VERSION 5.8 ;
BUSBITCHARS "[]" ;
DIVIDERCHAR "/" ;
UNITS
    DATABASE MICRONS 1000 ;
END UNITS

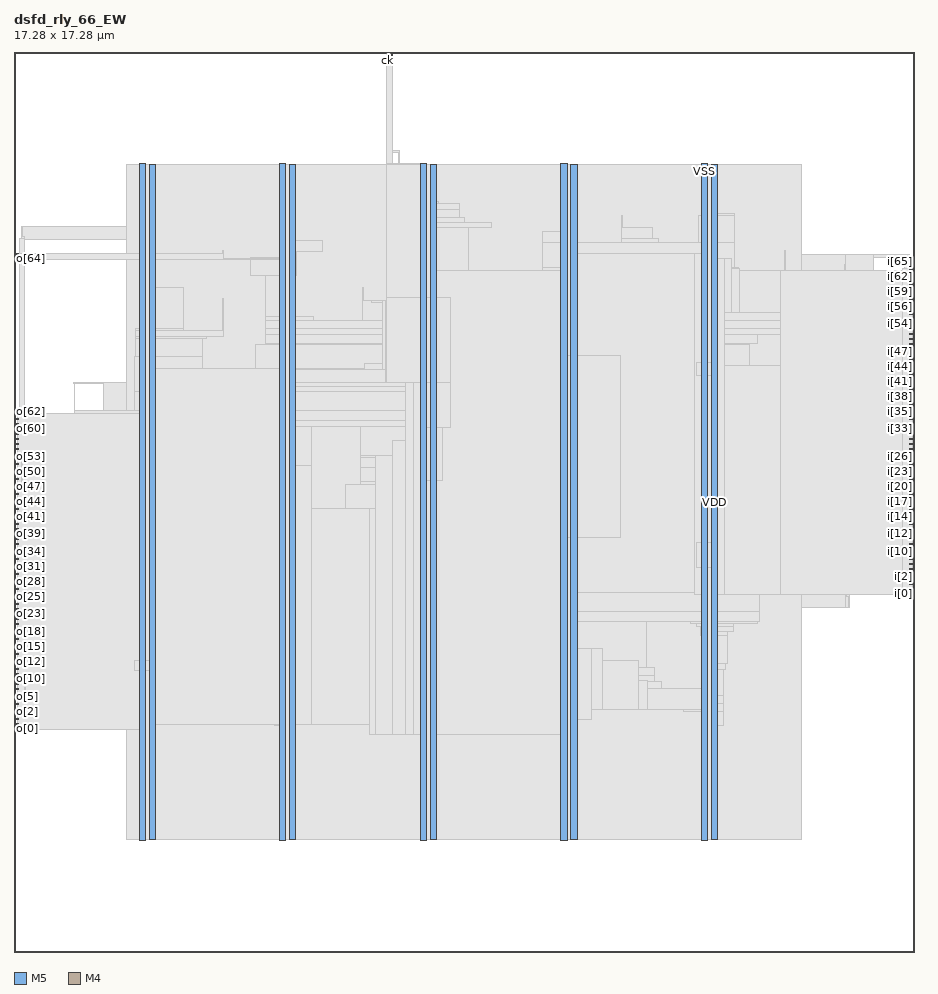
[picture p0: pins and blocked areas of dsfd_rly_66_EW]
MACRO dsfd_rly_66_EW
  FOREIGN dsfd_rly_66_EW 0 0 ;
  CLASS BLOCK ;
  SIZE 17.28 BY 17.28 ;
  PIN ck
    DIRECTION INPUT ;
    USE SIGNAL ;
    PORT
      LAYER M5 ;
        RECT  7.152 17.196 7.176 17.28 ;
    END
  END ck
  PIN i[0]
    DIRECTION INPUT ;
    USE SIGNAL ;
    PORT
      LAYER M4 ;
        RECT  17.196 6.864 17.28 6.888 ;
    END
  END i[0]
  PIN i[10]
    DIRECTION INPUT ;
    USE SIGNAL ;
    PORT
      LAYER M4 ;
        RECT  17.196 7.824 17.28 7.848 ;
    END
  END i[10]
  PIN i[11]
    DIRECTION INPUT ;
    USE SIGNAL ;
    PORT
      LAYER M4 ;
        RECT  17.196 7.92 17.28 7.944 ;
    END
  END i[11]
  PIN i[12]
    DIRECTION INPUT ;
    USE SIGNAL ;
    PORT
      LAYER M4 ;
        RECT  17.196 8.016 17.28 8.04 ;
    END
  END i[12]
  PIN i[13]
    DIRECTION INPUT ;
    USE SIGNAL ;
    PORT
      LAYER M4 ;
        RECT  17.196 8.112 17.28 8.136 ;
    END
  END i[13]
  PIN i[14]
    DIRECTION INPUT ;
    USE SIGNAL ;
    PORT
      LAYER M4 ;
        RECT  17.196 8.208 17.28 8.232 ;
    END
  END i[14]
  PIN i[15]
    DIRECTION INPUT ;
    USE SIGNAL ;
    PORT
      LAYER M4 ;
        RECT  17.196 8.304 17.28 8.328 ;
    END
  END i[15]
  PIN i[16]
    DIRECTION INPUT ;
    USE SIGNAL ;
    PORT
      LAYER M4 ;
        RECT  17.196 8.4 17.28 8.424 ;
    END
  END i[16]
  PIN i[17]
    DIRECTION INPUT ;
    USE SIGNAL ;
    PORT
      LAYER M4 ;
        RECT  17.196 8.496 17.28 8.52 ;
    END
  END i[17]
  PIN i[18]
    DIRECTION INPUT ;
    USE SIGNAL ;
    PORT
      LAYER M4 ;
        RECT  17.196 8.592 17.28 8.616 ;
    END
  END i[18]
  PIN i[19]
    DIRECTION INPUT ;
    USE SIGNAL ;
    PORT
      LAYER M4 ;
        RECT  17.196 8.688 17.28 8.712 ;
    END
  END i[19]
  PIN i[1]
    DIRECTION INPUT ;
    USE SIGNAL ;
    PORT
      LAYER M4 ;
        RECT  17.196 6.96 17.28 6.984 ;
    END
  END i[1]
  PIN i[20]
    DIRECTION INPUT ;
    USE SIGNAL ;
    PORT
      LAYER M4 ;
        RECT  17.196 8.784 17.28 8.808 ;
    END
  END i[20]
  PIN i[21]
    DIRECTION INPUT ;
    USE SIGNAL ;
    PORT
      LAYER M4 ;
        RECT  17.196 8.88 17.28 8.904 ;
    END
  END i[21]
  PIN i[22]
    DIRECTION INPUT ;
    USE SIGNAL ;
    PORT
      LAYER M4 ;
        RECT  17.196 8.976 17.28 9 ;
    END
  END i[22]
  PIN i[23]
    DIRECTION INPUT ;
    USE SIGNAL ;
    PORT
      LAYER M4 ;
        RECT  17.196 9.072 17.28 9.096 ;
    END
  END i[23]
  PIN i[24]
    DIRECTION INPUT ;
    USE SIGNAL ;
    PORT
      LAYER M4 ;
        RECT  17.196 9.168 17.28 9.192 ;
    END
  END i[24]
  PIN i[25]
    DIRECTION INPUT ;
    USE SIGNAL ;
    PORT
      LAYER M4 ;
        RECT  17.196 9.264 17.28 9.288 ;
    END
  END i[25]
  PIN i[26]
    DIRECTION INPUT ;
    USE SIGNAL ;
    PORT
      LAYER M4 ;
        RECT  17.196 9.36 17.28 9.384 ;
    END
  END i[26]
  PIN i[27]
    DIRECTION INPUT ;
    USE SIGNAL ;
    PORT
      LAYER M4 ;
        RECT  17.196 9.456 17.28 9.48 ;
    END
  END i[27]
  PIN i[28]
    DIRECTION INPUT ;
    USE SIGNAL ;
    PORT
      LAYER M4 ;
        RECT  17.196 9.552 17.28 9.576 ;
    END
  END i[28]
  PIN i[29]
    DIRECTION INPUT ;
    USE SIGNAL ;
    PORT
      LAYER M4 ;
        RECT  17.196 9.648 17.28 9.672 ;
    END
  END i[29]
  PIN i[2]
    DIRECTION INPUT ;
    USE SIGNAL ;
    PORT
      LAYER M4 ;
        RECT  17.196 7.056 17.28 7.08 ;
    END
  END i[2]
  PIN i[30]
    DIRECTION INPUT ;
    USE SIGNAL ;
    PORT
      LAYER M4 ;
        RECT  17.196 9.744 17.28 9.768 ;
    END
  END i[30]
  PIN i[31]
    DIRECTION INPUT ;
    USE SIGNAL ;
    PORT
      LAYER M4 ;
        RECT  17.196 9.84 17.28 9.864 ;
    END
  END i[31]
  PIN i[32]
    DIRECTION INPUT ;
    USE SIGNAL ;
    PORT
      LAYER M4 ;
        RECT  17.196 9.936 17.28 9.96 ;
    END
  END i[32]
  PIN i[33]
    DIRECTION INPUT ;
    USE SIGNAL ;
    PORT
      LAYER M4 ;
        RECT  17.196 10.032 17.28 10.056 ;
    END
  END i[33]
  PIN i[34]
    DIRECTION INPUT ;
    USE SIGNAL ;
    PORT
      LAYER M4 ;
        RECT  17.196 10.128 17.28 10.152 ;
    END
  END i[34]
  PIN i[35]
    DIRECTION INPUT ;
    USE SIGNAL ;
    PORT
      LAYER M4 ;
        RECT  17.196 10.224 17.28 10.248 ;
    END
  END i[35]
  PIN i[36]
    DIRECTION INPUT ;
    USE SIGNAL ;
    PORT
      LAYER M4 ;
        RECT  17.196 10.32 17.28 10.344 ;
    END
  END i[36]
  PIN i[37]
    DIRECTION INPUT ;
    USE SIGNAL ;
    PORT
      LAYER M4 ;
        RECT  17.196 10.416 17.28 10.44 ;
    END
  END i[37]
  PIN i[38]
    DIRECTION INPUT ;
    USE SIGNAL ;
    PORT
      LAYER M4 ;
        RECT  17.196 10.512 17.28 10.536 ;
    END
  END i[38]
  PIN i[39]
    DIRECTION INPUT ;
    USE SIGNAL ;
    PORT
      LAYER M4 ;
        RECT  17.196 10.608 17.28 10.632 ;
    END
  END i[39]
  PIN i[3]
    DIRECTION INPUT ;
    USE SIGNAL ;
    PORT
      LAYER M4 ;
        RECT  17.196 7.152 17.28 7.176 ;
    END
  END i[3]
  PIN i[40]
    DIRECTION INPUT ;
    USE SIGNAL ;
    PORT
      LAYER M4 ;
        RECT  17.196 10.704 17.28 10.728 ;
    END
  END i[40]
  PIN i[41]
    DIRECTION INPUT ;
    USE SIGNAL ;
    PORT
      LAYER M4 ;
        RECT  17.196 10.8 17.28 10.824 ;
    END
  END i[41]
  PIN i[42]
    DIRECTION INPUT ;
    USE SIGNAL ;
    PORT
      LAYER M4 ;
        RECT  17.196 10.896 17.28 10.92 ;
    END
  END i[42]
  PIN i[43]
    DIRECTION INPUT ;
    USE SIGNAL ;
    PORT
      LAYER M4 ;
        RECT  17.196 10.992 17.28 11.016 ;
    END
  END i[43]
  PIN i[44]
    DIRECTION INPUT ;
    USE SIGNAL ;
    PORT
      LAYER M4 ;
        RECT  17.196 11.088 17.28 11.112 ;
    END
  END i[44]
  PIN i[45]
    DIRECTION INPUT ;
    USE SIGNAL ;
    PORT
      LAYER M4 ;
        RECT  17.196 11.184 17.28 11.208 ;
    END
  END i[45]
  PIN i[46]
    DIRECTION INPUT ;
    USE SIGNAL ;
    PORT
      LAYER M4 ;
        RECT  17.196 11.28 17.28 11.304 ;
    END
  END i[46]
  PIN i[47]
    DIRECTION INPUT ;
    USE SIGNAL ;
    PORT
      LAYER M4 ;
        RECT  17.196 11.376 17.28 11.4 ;
    END
  END i[47]
  PIN i[48]
    DIRECTION INPUT ;
    USE SIGNAL ;
    PORT
      LAYER M4 ;
        RECT  17.196 11.472 17.28 11.496 ;
    END
  END i[48]
  PIN i[49]
    DIRECTION INPUT ;
    USE SIGNAL ;
    PORT
      LAYER M4 ;
        RECT  17.196 11.568 17.28 11.592 ;
    END
  END i[49]
  PIN i[4]
    DIRECTION INPUT ;
    USE SIGNAL ;
    PORT
      LAYER M4 ;
        RECT  17.196 7.248 17.28 7.272 ;
    END
  END i[4]
  PIN i[50]
    DIRECTION INPUT ;
    USE SIGNAL ;
    PORT
      LAYER M4 ;
        RECT  17.196 11.664 17.28 11.688 ;
    END
  END i[50]
  PIN i[51]
    DIRECTION INPUT ;
    USE SIGNAL ;
    PORT
      LAYER M4 ;
        RECT  17.196 11.76 17.28 11.784 ;
    END
  END i[51]
  PIN i[52]
    DIRECTION INPUT ;
    USE SIGNAL ;
    PORT
      LAYER M4 ;
        RECT  17.196 11.856 17.28 11.88 ;
    END
  END i[52]
  PIN i[53]
    DIRECTION INPUT ;
    USE SIGNAL ;
    PORT
      LAYER M4 ;
        RECT  17.196 11.952 17.28 11.976 ;
    END
  END i[53]
  PIN i[54]
    DIRECTION INPUT ;
    USE SIGNAL ;
    PORT
      LAYER M4 ;
        RECT  17.196 12.048 17.28 12.072 ;
    END
  END i[54]
  PIN i[55]
    DIRECTION INPUT ;
    USE SIGNAL ;
    PORT
      LAYER M4 ;
        RECT  17.196 12.144 17.28 12.168 ;
    END
  END i[55]
  PIN i[56]
    DIRECTION INPUT ;
    USE SIGNAL ;
    PORT
      LAYER M4 ;
        RECT  17.196 12.24 17.28 12.264 ;
    END
  END i[56]
  PIN i[57]
    DIRECTION INPUT ;
    USE SIGNAL ;
    PORT
      LAYER M4 ;
        RECT  17.196 12.336 17.28 12.36 ;
    END
  END i[57]
  PIN i[58]
    DIRECTION INPUT ;
    USE SIGNAL ;
    PORT
      LAYER M4 ;
        RECT  17.196 12.432 17.28 12.456 ;
    END
  END i[58]
  PIN i[59]
    DIRECTION INPUT ;
    USE SIGNAL ;
    PORT
      LAYER M4 ;
        RECT  17.196 12.528 17.28 12.552 ;
    END
  END i[59]
  PIN i[5]
    DIRECTION INPUT ;
    USE SIGNAL ;
    PORT
      LAYER M4 ;
        RECT  17.196 7.344 17.28 7.368 ;
    END
  END i[5]
  PIN i[60]
    DIRECTION INPUT ;
    USE SIGNAL ;
    PORT
      LAYER M4 ;
        RECT  17.196 12.624 17.28 12.648 ;
    END
  END i[60]
  PIN i[61]
    DIRECTION INPUT ;
    USE SIGNAL ;
    PORT
      LAYER M4 ;
        RECT  17.196 12.72 17.28 12.744 ;
    END
  END i[61]
  PIN i[62]
    DIRECTION INPUT ;
    USE SIGNAL ;
    PORT
      LAYER M4 ;
        RECT  17.196 12.816 17.28 12.84 ;
    END
  END i[62]
  PIN i[63]
    DIRECTION INPUT ;
    USE SIGNAL ;
    PORT
      LAYER M4 ;
        RECT  17.196 12.912 17.28 12.936 ;
    END
  END i[63]
  PIN i[64]
    DIRECTION INPUT ;
    USE SIGNAL ;
    PORT
      LAYER M4 ;
        RECT  17.196 13.008 17.28 13.032 ;
    END
  END i[64]
  PIN i[65]
    DIRECTION INPUT ;
    USE SIGNAL ;
    PORT
      LAYER M4 ;
        RECT  17.196 13.104 17.28 13.128 ;
    END
  END i[65]
  PIN i[6]
    DIRECTION INPUT ;
    USE SIGNAL ;
    PORT
      LAYER M4 ;
        RECT  17.196 7.44 17.28 7.464 ;
    END
  END i[6]
  PIN i[7]
    DIRECTION INPUT ;
    USE SIGNAL ;
    PORT
      LAYER M4 ;
        RECT  17.196 7.536 17.28 7.56 ;
    END
  END i[7]
  PIN i[8]
    DIRECTION INPUT ;
    USE SIGNAL ;
    PORT
      LAYER M4 ;
        RECT  17.196 7.632 17.28 7.656 ;
    END
  END i[8]
  PIN i[9]
    DIRECTION INPUT ;
    USE SIGNAL ;
    PORT
      LAYER M4 ;
        RECT  17.196 7.728 17.28 7.752 ;
    END
  END i[9]
  PIN o[0]
    DIRECTION OUTPUT ;
    USE SIGNAL ;
    PORT
      LAYER M4 ;
        RECT  0 4.272 0.084 4.296 ;
    END
  END o[0]
  PIN o[10]
    DIRECTION OUTPUT ;
    USE SIGNAL ;
    PORT
      LAYER M4 ;
        RECT  0 5.232 0.084 5.256 ;
    END
  END o[10]
  PIN o[11]
    DIRECTION OUTPUT ;
    USE SIGNAL ;
    PORT
      LAYER M4 ;
        RECT  0 5.328 0.084 5.352 ;
    END
  END o[11]
  PIN o[12]
    DIRECTION OUTPUT ;
    USE SIGNAL ;
    PORT
      LAYER M4 ;
        RECT  0 5.424 0.084 5.448 ;
    END
  END o[12]
  PIN o[13]
    DIRECTION OUTPUT ;
    USE SIGNAL ;
    PORT
      LAYER M4 ;
        RECT  0 5.52 0.084 5.544 ;
    END
  END o[13]
  PIN o[14]
    DIRECTION OUTPUT ;
    USE SIGNAL ;
    PORT
      LAYER M4 ;
        RECT  0 5.616 0.084 5.64 ;
    END
  END o[14]
  PIN o[15]
    DIRECTION OUTPUT ;
    USE SIGNAL ;
    PORT
      LAYER M4 ;
        RECT  0 5.712 0.084 5.736 ;
    END
  END o[15]
  PIN o[16]
    DIRECTION OUTPUT ;
    USE SIGNAL ;
    PORT
      LAYER M4 ;
        RECT  0 5.808 0.084 5.832 ;
    END
  END o[16]
  PIN o[17]
    DIRECTION OUTPUT ;
    USE SIGNAL ;
    PORT
      LAYER M4 ;
        RECT  0 5.904 0.084 5.928 ;
    END
  END o[17]
  PIN o[18]
    DIRECTION OUTPUT ;
    USE SIGNAL ;
    PORT
      LAYER M4 ;
        RECT  0 6 0.084 6.024 ;
    END
  END o[18]
  PIN o[19]
    DIRECTION OUTPUT ;
    USE SIGNAL ;
    PORT
      LAYER M4 ;
        RECT  0 6.096 0.084 6.12 ;
    END
  END o[19]
  PIN o[1]
    DIRECTION OUTPUT ;
    USE SIGNAL ;
    PORT
      LAYER M4 ;
        RECT  0 4.368 0.084 4.392 ;
    END
  END o[1]
  PIN o[20]
    DIRECTION OUTPUT ;
    USE SIGNAL ;
    PORT
      LAYER M4 ;
        RECT  0 6.192 0.084 6.216 ;
    END
  END o[20]
  PIN o[21]
    DIRECTION OUTPUT ;
    USE SIGNAL ;
    PORT
      LAYER M4 ;
        RECT  0 6.288 0.084 6.312 ;
    END
  END o[21]
  PIN o[22]
    DIRECTION OUTPUT ;
    USE SIGNAL ;
    PORT
      LAYER M4 ;
        RECT  0 6.384 0.084 6.408 ;
    END
  END o[22]
  PIN o[23]
    DIRECTION OUTPUT ;
    USE SIGNAL ;
    PORT
      LAYER M4 ;
        RECT  0 6.48 0.084 6.504 ;
    END
  END o[23]
  PIN o[24]
    DIRECTION OUTPUT ;
    USE SIGNAL ;
    PORT
      LAYER M4 ;
        RECT  0 6.576 0.084 6.6 ;
    END
  END o[24]
  PIN o[25]
    DIRECTION OUTPUT ;
    USE SIGNAL ;
    PORT
      LAYER M4 ;
        RECT  0 6.672 0.084 6.696 ;
    END
  END o[25]
  PIN o[26]
    DIRECTION OUTPUT ;
    USE SIGNAL ;
    PORT
      LAYER M4 ;
        RECT  0 6.768 0.084 6.792 ;
    END
  END o[26]
  PIN o[27]
    DIRECTION OUTPUT ;
    USE SIGNAL ;
    PORT
      LAYER M4 ;
        RECT  0 6.864 0.084 6.888 ;
    END
  END o[27]
  PIN o[28]
    DIRECTION OUTPUT ;
    USE SIGNAL ;
    PORT
      LAYER M4 ;
        RECT  0 6.96 0.084 6.984 ;
    END
  END o[28]
  PIN o[29]
    DIRECTION OUTPUT ;
    USE SIGNAL ;
    PORT
      LAYER M4 ;
        RECT  0 7.056 0.084 7.08 ;
    END
  END o[29]
  PIN o[2]
    DIRECTION OUTPUT ;
    USE SIGNAL ;
    PORT
      LAYER M4 ;
        RECT  0 4.464 0.084 4.488 ;
    END
  END o[2]
  PIN o[30]
    DIRECTION OUTPUT ;
    USE SIGNAL ;
    PORT
      LAYER M4 ;
        RECT  0 7.152 0.084 7.176 ;
    END
  END o[30]
  PIN o[31]
    DIRECTION OUTPUT ;
    USE SIGNAL ;
    PORT
      LAYER M4 ;
        RECT  0 7.248 0.084 7.272 ;
    END
  END o[31]
  PIN o[32]
    DIRECTION OUTPUT ;
    USE SIGNAL ;
    PORT
      LAYER M4 ;
        RECT  0 7.344 0.084 7.368 ;
    END
  END o[32]
  PIN o[33]
    DIRECTION OUTPUT ;
    USE SIGNAL ;
    PORT
      LAYER M4 ;
        RECT  0 7.44 0.084 7.464 ;
    END
  END o[33]
  PIN o[34]
    DIRECTION OUTPUT ;
    USE SIGNAL ;
    PORT
      LAYER M4 ;
        RECT  0 7.536 0.084 7.56 ;
    END
  END o[34]
  PIN o[35]
    DIRECTION OUTPUT ;
    USE SIGNAL ;
    PORT
      LAYER M4 ;
        RECT  0 7.632 0.084 7.656 ;
    END
  END o[35]
  PIN o[36]
    DIRECTION OUTPUT ;
    USE SIGNAL ;
    PORT
      LAYER M4 ;
        RECT  0 7.728 0.084 7.752 ;
    END
  END o[36]
  PIN o[37]
    DIRECTION OUTPUT ;
    USE SIGNAL ;
    PORT
      LAYER M4 ;
        RECT  0 7.824 0.084 7.848 ;
    END
  END o[37]
  PIN o[38]
    DIRECTION OUTPUT ;
    USE SIGNAL ;
    PORT
      LAYER M4 ;
        RECT  0 7.92 0.084 7.944 ;
    END
  END o[38]
  PIN o[39]
    DIRECTION OUTPUT ;
    USE SIGNAL ;
    PORT
      LAYER M4 ;
        RECT  0 8.016 0.084 8.04 ;
    END
  END o[39]
  PIN o[3]
    DIRECTION OUTPUT ;
    USE SIGNAL ;
    PORT
      LAYER M4 ;
        RECT  0 4.56 0.084 4.584 ;
    END
  END o[3]
  PIN o[40]
    DIRECTION OUTPUT ;
    USE SIGNAL ;
    PORT
      LAYER M4 ;
        RECT  0 8.112 0.084 8.136 ;
    END
  END o[40]
  PIN o[41]
    DIRECTION OUTPUT ;
    USE SIGNAL ;
    PORT
      LAYER M4 ;
        RECT  0 8.208 0.084 8.232 ;
    END
  END o[41]
  PIN o[42]
    DIRECTION OUTPUT ;
    USE SIGNAL ;
    PORT
      LAYER M4 ;
        RECT  0 8.304 0.084 8.328 ;
    END
  END o[42]
  PIN o[43]
    DIRECTION OUTPUT ;
    USE SIGNAL ;
    PORT
      LAYER M4 ;
        RECT  0 8.4 0.084 8.424 ;
    END
  END o[43]
  PIN o[44]
    DIRECTION OUTPUT ;
    USE SIGNAL ;
    PORT
      LAYER M4 ;
        RECT  0 8.496 0.084 8.52 ;
    END
  END o[44]
  PIN o[45]
    DIRECTION OUTPUT ;
    USE SIGNAL ;
    PORT
      LAYER M4 ;
        RECT  0 8.592 0.084 8.616 ;
    END
  END o[45]
  PIN o[46]
    DIRECTION OUTPUT ;
    USE SIGNAL ;
    PORT
      LAYER M4 ;
        RECT  0 8.688 0.084 8.712 ;
    END
  END o[46]
  PIN o[47]
    DIRECTION OUTPUT ;
    USE SIGNAL ;
    PORT
      LAYER M4 ;
        RECT  0 8.784 0.084 8.808 ;
    END
  END o[47]
  PIN o[48]
    DIRECTION OUTPUT ;
    USE SIGNAL ;
    PORT
      LAYER M4 ;
        RECT  0 8.88 0.084 8.904 ;
    END
  END o[48]
  PIN o[49]
    DIRECTION OUTPUT ;
    USE SIGNAL ;
    PORT
      LAYER M4 ;
        RECT  0 8.976 0.084 9 ;
    END
  END o[49]
  PIN o[4]
    DIRECTION OUTPUT ;
    USE SIGNAL ;
    PORT
      LAYER M4 ;
        RECT  0 4.656 0.084 4.68 ;
    END
  END o[4]
  PIN o[50]
    DIRECTION OUTPUT ;
    USE SIGNAL ;
    PORT
      LAYER M4 ;
        RECT  0 9.072 0.084 9.096 ;
    END
  END o[50]
  PIN o[51]
    DIRECTION OUTPUT ;
    USE SIGNAL ;
    PORT
      LAYER M4 ;
        RECT  0 9.168 0.084 9.192 ;
    END
  END o[51]
  PIN o[52]
    DIRECTION OUTPUT ;
    USE SIGNAL ;
    PORT
      LAYER M4 ;
        RECT  0 9.264 0.084 9.288 ;
    END
  END o[52]
  PIN o[53]
    DIRECTION OUTPUT ;
    USE SIGNAL ;
    PORT
      LAYER M4 ;
        RECT  0 9.36 0.084 9.384 ;
    END
  END o[53]
  PIN o[54]
    DIRECTION OUTPUT ;
    USE SIGNAL ;
    PORT
      LAYER M4 ;
        RECT  0 9.456 0.084 9.48 ;
    END
  END o[54]
  PIN o[55]
    DIRECTION OUTPUT ;
    USE SIGNAL ;
    PORT
      LAYER M4 ;
        RECT  0 9.552 0.084 9.576 ;
    END
  END o[55]
  PIN o[56]
    DIRECTION OUTPUT ;
    USE SIGNAL ;
    PORT
      LAYER M4 ;
        RECT  0 9.648 0.084 9.672 ;
    END
  END o[56]
  PIN o[57]
    DIRECTION OUTPUT ;
    USE SIGNAL ;
    PORT
      LAYER M4 ;
        RECT  0 9.744 0.084 9.768 ;
    END
  END o[57]
  PIN o[58]
    DIRECTION OUTPUT ;
    USE SIGNAL ;
    PORT
      LAYER M4 ;
        RECT  0 9.84 0.084 9.864 ;
    END
  END o[58]
  PIN o[59]
    DIRECTION OUTPUT ;
    USE SIGNAL ;
    PORT
      LAYER M4 ;
        RECT  0 9.936 0.084 9.96 ;
    END
  END o[59]
  PIN o[5]
    DIRECTION OUTPUT ;
    USE SIGNAL ;
    PORT
      LAYER M4 ;
        RECT  0 4.752 0.084 4.776 ;
    END
  END o[5]
  PIN o[60]
    DIRECTION OUTPUT ;
    USE SIGNAL ;
    PORT
      LAYER M4 ;
        RECT  0 10.032 0.084 10.056 ;
    END
  END o[60]
  PIN o[61]
    DIRECTION OUTPUT ;
    USE SIGNAL ;
    PORT
      LAYER M4 ;
        RECT  0 10.128 0.084 10.152 ;
    END
  END o[61]
  PIN o[62]
    DIRECTION OUTPUT ;
    USE SIGNAL ;
    PORT
      LAYER M4 ;
        RECT  0 10.224 0.084 10.248 ;
    END
  END o[62]
  PIN o[63]
    DIRECTION OUTPUT ;
    USE SIGNAL ;
    PORT
      LAYER M4 ;
        RECT  0 10.32 0.084 10.344 ;
    END
  END o[63]
  PIN o[64]
    DIRECTION OUTPUT ;
    USE SIGNAL ;
    PORT
      LAYER M4 ;
        RECT  0 13.296 0.084 13.32 ;
    END
  END o[64]
  PIN o[65]
    DIRECTION OUTPUT ;
    USE SIGNAL ;
    PORT
      LAYER M4 ;
        RECT  0 13.392 0.084 13.416 ;
    END
  END o[65]
  PIN o[6]
    DIRECTION OUTPUT ;
    USE SIGNAL ;
    PORT
      LAYER M4 ;
        RECT  0 4.848 0.084 4.872 ;
    END
  END o[6]
  PIN o[7]
    DIRECTION OUTPUT ;
    USE SIGNAL ;
    PORT
      LAYER M4 ;
        RECT  0 4.944 0.084 4.968 ;
    END
  END o[7]
  PIN o[8]
    DIRECTION OUTPUT ;
    USE SIGNAL ;
    PORT
      LAYER M4 ;
        RECT  0 5.04 0.084 5.064 ;
    END
  END o[8]
  PIN o[9]
    DIRECTION OUTPUT ;
    USE SIGNAL ;
    PORT
      LAYER M4 ;
        RECT  0 5.136 0.084 5.16 ;
    END
  END o[9]
  PIN rs
    DIRECTION INPUT ;
    USE SIGNAL ;
    PORT
      LAYER M5 ;
        RECT  7.248 17.196 7.272 17.28 ;
    END
  END rs
  PIN VDD
    DIRECTION INOUT ;
    USE POWER ;
    PORT
      LAYER M5 ;
        RECT  13.392 2.151 13.512 15.129 ;
        RECT  10.692 2.151 10.812 15.129 ;
        RECT  7.992 2.151 8.112 15.129 ;
        RECT  5.292 2.151 5.412 15.129 ;
        RECT  2.592 2.151 2.712 15.129 ;
    END
  END VDD
  PIN VSS
    DIRECTION INOUT ;
    USE GROUND ;
    PORT
      LAYER M5 ;
        RECT  13.2 2.137 13.32 15.143 ;
        RECT  10.5 2.137 10.62 15.143 ;
        RECT  7.8 2.137 7.92 15.143 ;
        RECT  5.1 2.137 5.22 15.143 ;
        RECT  2.4 2.137 2.52 15.143 ;
    END
  END VSS
  OBS
    LAYER RVTN ;
     RECT  2.16 2.16 15.12 2.295 ;
     RECT  2.16 2.565 15.12 2.835 ;
     RECT  2.16 3.105 15.12 3.375 ;
     RECT  2.16 3.645 15.12 3.915 ;
     RECT  2.16 4.185 15.12 4.455 ;
     RECT  2.16 4.725 15.12 4.995 ;
     RECT  2.16 5.265 15.12 5.535 ;
     RECT  2.16 5.805 15.12 6.075 ;
     RECT  2.16 6.345 15.12 6.615 ;
     RECT  2.16 6.885 15.12 7.155 ;
     RECT  2.16 7.425 15.12 7.695 ;
     RECT  2.16 7.965 15.12 8.235 ;
     RECT  2.16 8.505 15.12 8.775 ;
     RECT  2.16 9.045 15.12 9.315 ;
     RECT  2.16 9.585 15.12 9.855 ;
     RECT  2.16 10.125 15.12 10.395 ;
     RECT  2.16 10.665 15.12 10.935 ;
     RECT  2.16 11.205 15.12 11.475 ;
     RECT  2.16 11.745 15.12 12.015 ;
     RECT  2.16 12.285 15.12 12.555 ;
     RECT  2.16 12.825 15.12 13.095 ;
     RECT  2.16 13.365 15.12 13.635 ;
     RECT  2.16 13.905 15.12 14.175 ;
     RECT  2.16 14.445 15.12 14.715 ;
     RECT  2.16 14.985 15.12 15.12 ;
    LAYER RVTP ;
     RECT  2.16 2.295 15.12 2.565 ;
     RECT  2.16 2.835 15.12 3.105 ;
     RECT  2.16 3.375 15.12 3.645 ;
     RECT  2.16 3.915 15.12 4.185 ;
     RECT  2.16 4.455 15.12 4.725 ;
     RECT  2.16 4.995 15.12 5.265 ;
     RECT  2.16 5.535 15.12 5.805 ;
     RECT  2.16 6.075 15.12 6.345 ;
     RECT  2.16 6.615 15.12 6.885 ;
     RECT  2.16 7.155 15.12 7.425 ;
     RECT  2.16 7.695 15.12 7.965 ;
     RECT  2.16 8.235 15.12 8.505 ;
     RECT  2.16 8.775 15.12 9.045 ;
     RECT  2.16 9.315 15.12 9.585 ;
     RECT  2.16 9.855 15.12 10.125 ;
     RECT  2.16 10.395 15.12 10.665 ;
     RECT  2.16 10.935 15.12 11.205 ;
     RECT  2.16 11.475 15.12 11.745 ;
     RECT  2.16 12.015 15.12 12.285 ;
     RECT  2.16 12.555 15.12 12.825 ;
     RECT  2.16 13.095 15.12 13.365 ;
     RECT  2.16 13.635 15.12 13.905 ;
     RECT  2.16 14.175 15.12 14.445 ;
     RECT  2.16 14.715 15.12 14.985 ;
    LAYER M1 ;
     RECT  2.16 2.151 15.12 15.129 ;
    LAYER M2 ;
     RECT  0.103 8.982 0.139 9 ;
     RECT  0.103 13.68 0.139 13.698 ;
     RECT  0.103 5.391 0.175 5.409 ;
     RECT  0.175 5.04 0.203 5.409 ;
     RECT  0.103 6.66 0.211 6.876 ;
     RECT  0.211 6.588 0.239 6.876 ;
     RECT  0.203 5.04 0.347 5.058 ;
     RECT  0.239 6.588 0.499 6.606 ;
     RECT  0.139 8.982 1.147 9.072 ;
     RECT  1.147 10.908 1.723 10.926 ;
     RECT  0.499 6.048 2.16 6.606 ;
     RECT  1.147 8.406 2.16 9.072 ;
     RECT  1.723 10.368 2.16 10.926 ;
     RECT  0.139 13.68 2.16 13.932 ;
     RECT  2.16 2.151 15.12 15.129 ;
     RECT  15.12 6.624 15.971 13.392 ;
     RECT  15.971 6.624 16.043 9.954 ;
     RECT  16.043 7.164 16.079 9.954 ;
     RECT  15.971 10.908 16.403 11.574 ;
     RECT  15.971 12.528 16.511 13.392 ;
     RECT  16.079 7.74 16.547 9.954 ;
     RECT  16.403 11.178 16.547 11.574 ;
     RECT  16.547 8.28 17.095 9.954 ;
     RECT  16.511 13.338 17.123 13.392 ;
     RECT  16.547 11.178 17.159 11.232 ;
     RECT  17.095 7.506 17.195 7.524 ;
     RECT  17.095 8.28 17.195 10.224 ;
     RECT  17.159 11.214 17.195 11.232 ;
     RECT  16.511 12.528 17.195 12.546 ;
     RECT  17.123 13.374 17.195 13.392 ;
    LAYER M3 ;
     RECT  2.415 2.143 2.505 2.413 ;
     RECT  5.115 2.143 5.205 2.413 ;
     RECT  7.815 2.143 7.905 2.413 ;
     RECT  10.515 2.143 10.605 2.413 ;
     RECT  13.215 2.143 13.305 2.413 ;
     RECT  2.415 2.413 2.697 4.267 ;
     RECT  5.115 2.413 5.397 4.351 ;
     RECT  13.215 2.413 13.497 4.351 ;
     RECT  6.84 4.171 6.858 4.363 ;
     RECT  5.004 4.351 5.397 4.397 ;
     RECT  10.515 2.413 10.797 4.459 ;
     RECT  6.84 4.363 6.966 4.493 ;
     RECT  2.268 4.267 2.697 4.559 ;
     RECT  13.215 4.351 13.626 4.621 ;
     RECT  12.852 4.621 13.626 4.765 ;
     RECT  0.144 4.555 0.162 4.843 ;
     RECT  3.996 4.699 4.014 4.891 ;
     RECT  9.72 4.171 9.738 4.891 ;
     RECT  10.515 4.459 11.07 4.891 ;
     RECT  9.72 4.891 11.07 4.919 ;
     RECT  12.708 4.765 13.626 4.919 ;
     RECT  2.304 4.559 2.697 4.939 ;
     RECT  3.456 4.891 4.014 4.939 ;
     RECT  7.815 2.413 8.097 4.939 ;
     RECT  8.928 4.765 8.946 4.939 ;
     RECT  9.936 4.919 11.07 4.991 ;
     RECT  10.116 4.991 11.07 5.035 ;
     RECT  11.916 4.747 11.934 5.035 ;
     RECT  0.144 4.843 0.342 5.069 ;
     RECT  0.144 5.069 0.198 5.131 ;
     RECT  11.916 5.035 12.438 5.189 ;
     RECT  2.304 4.939 4.014 5.305 ;
     RECT  5.115 4.397 5.397 5.305 ;
     RECT  10.116 5.035 11.106 5.305 ;
     RECT  11.916 5.189 12.294 5.305 ;
     RECT  0.108 5.131 0.198 5.42 ;
     RECT  13.215 4.919 13.626 5.431 ;
     RECT  2.304 5.305 5.397 5.459 ;
     RECT  10.116 5.305 12.294 5.459 ;
     RECT  1.26 5.323 1.278 5.501 ;
     RECT  13.215 5.431 13.662 5.539 ;
     RECT  7.815 4.939 8.946 5.567 ;
     RECT  3.996 5.459 5.397 5.575 ;
     RECT  8.928 5.567 8.946 5.611 ;
     RECT  6.804 5.503 6.822 5.701 ;
     RECT  7.815 5.567 8.19 5.701 ;
     RECT  3.996 5.575 5.742 5.845 ;
     RECT  6.804 5.701 8.19 5.845 ;
     RECT  2.304 5.459 3.222 6.029 ;
     RECT  1.152 5.899 1.17 6.043 ;
     RECT  13.215 5.539 13.698 6.079 ;
     RECT  13.176 6.079 13.698 6.151 ;
     RECT  13.176 6.151 13.806 6.241 ;
     RECT  3.996 5.845 8.19 6.269 ;
     RECT  13.104 6.241 13.806 6.313 ;
     RECT  10.116 5.459 12.15 6.349 ;
     RECT  12.996 6.313 14.274 6.349 ;
     RECT  6.84 6.269 8.19 6.385 ;
     RECT  8.928 5.611 9.054 6.385 ;
     RECT  0.504 6.043 1.17 6.475 ;
     RECT  10.116 6.349 14.31 6.547 ;
     RECT  2.415 6.029 3.222 6.583 ;
     RECT  3.996 6.269 6.03 6.583 ;
     RECT  0.144 6.475 1.17 6.652 ;
     RECT  6.84 6.385 9.054 6.683 ;
     RECT  16.02 6.619 16.038 6.817 ;
     RECT  7.488 6.683 9.054 6.845 ;
     RECT  7.74 6.845 9.054 6.907 ;
     RECT  10.008 6.547 14.31 6.907 ;
     RECT  2.415 6.583 6.03 6.955 ;
     RECT  2.304 6.955 6.03 7.051 ;
     RECT  15.984 6.817 16.038 7.159 ;
     RECT  2.268 7.051 6.03 7.231 ;
     RECT  7.74 6.907 14.31 7.357 ;
     RECT  17.1 7.483 17.118 7.501 ;
     RECT  7.74 7.357 14.526 7.591 ;
     RECT  2.268 7.231 6.354 7.663 ;
     RECT  7.74 7.591 14.85 7.675 ;
     RECT  2.268 7.663 6.498 7.735 ;
     RECT  7.308 7.675 14.85 7.735 ;
     RECT  15.984 7.159 16.074 7.735 ;
     RECT  17.1 7.501 17.19 7.735 ;
     RECT  0.108 6.652 1.17 7.819 ;
     RECT  2.268 7.735 14.85 7.819 ;
     RECT  15.984 7.735 17.19 7.853 ;
     RECT  17.1 7.853 17.19 7.949 ;
     RECT  0.108 7.819 14.85 8.141 ;
     RECT  15.984 7.853 16.038 8.141 ;
     RECT  1.152 8.141 14.85 8.239 ;
     RECT  15.984 8.141 16.002 8.239 ;
     RECT  1.152 8.239 16.002 8.429 ;
     RECT  6.372 8.429 16.002 8.969 ;
     RECT  6.66 8.969 16.002 9.041 ;
     RECT  17.172 7.949 17.19 9.067 ;
     RECT  17.136 9.067 17.19 9.113 ;
     RECT  6.66 9.041 14.454 9.293 ;
     RECT  1.152 8.429 5.634 9.307 ;
     RECT  15.372 9.041 16.002 9.347 ;
     RECT  0.108 8.141 0.342 9.581 ;
     RECT  15.372 9.347 15.966 9.922 ;
     RECT  1.152 9.307 5.706 10.093 ;
     RECT  6.66 9.293 14.274 10.093 ;
     RECT  17.172 9.113 17.19 10.171 ;
     RECT  1.152 10.093 14.274 10.201 ;
     RECT  17.1 10.171 17.19 10.253 ;
     RECT  1.152 10.201 14.382 10.391 ;
     RECT  15.336 9.922 15.966 10.411 ;
     RECT  15.3 10.411 15.966 10.661 ;
     RECT  15.3 10.661 15.57 10.733 ;
     RECT  2.304 10.391 14.382 10.769 ;
     RECT  17.1 10.253 17.118 10.795 ;
     RECT  4.536 10.769 14.382 10.859 ;
     RECT  1.152 10.391 1.17 10.931 ;
     RECT  4.536 10.859 14.13 10.931 ;
     RECT  16.38 10.795 17.118 10.931 ;
     RECT  16.524 10.931 17.118 10.987 ;
     RECT  15.336 10.733 15.57 11.003 ;
     RECT  16.524 10.987 17.19 11.237 ;
     RECT  16.524 11.237 17.01 11.405 ;
     RECT  2.304 10.769 3.618 11.435 ;
     RECT  15.336 11.003 15.426 11.659 ;
     RECT  4.644 10.931 14.13 11.669 ;
     RECT  4.824 11.669 14.13 11.677 ;
     RECT  2.34 11.435 3.618 11.785 ;
     RECT  2.34 11.785 3.69 11.821 ;
     RECT  4.824 11.677 14.274 11.851 ;
     RECT  15.3 11.659 15.426 11.851 ;
     RECT  2.34 11.821 4.014 11.939 ;
     RECT  2.34 11.939 3.258 11.975 ;
     RECT  4.824 11.851 15.426 11.975 ;
     RECT  16.524 11.405 16.542 12.043 ;
     RECT  4.824 11.975 14.922 12.119 ;
     RECT  15.66 12.043 16.542 12.139 ;
     RECT  4.824 12.119 5.742 12.209 ;
     RECT  15.66 12.139 17.118 12.331 ;
     RECT  6.696 12.119 14.922 12.509 ;
     RECT  7.596 12.509 14.922 12.515 ;
     RECT  3.996 11.939 4.014 12.551 ;
     RECT  2.415 11.975 3.258 12.749 ;
     RECT  6.696 12.509 6.714 12.749 ;
     RECT  7.74 12.515 14.922 12.749 ;
     RECT  15.66 12.331 17.19 12.821 ;
     RECT  15.66 12.821 16.002 12.845 ;
     RECT  15.66 12.845 15.966 12.929 ;
     RECT  4.824 12.209 5.397 12.991 ;
     RECT  7.74 12.749 14.814 13.019 ;
     RECT  10.152 13.019 14.814 13.055 ;
     RECT  17.028 12.821 17.19 13.085 ;
     RECT  7.74 13.019 9.378 13.091 ;
     RECT  14.724 13.055 14.814 13.091 ;
     RECT  10.152 13.055 13.914 13.133 ;
     RECT  15.948 12.929 15.966 13.199 ;
     RECT  4.536 12.991 5.418 13.325 ;
     RECT  17.1 13.085 17.19 13.361 ;
     RECT  17.172 13.361 17.19 13.397 ;
     RECT  5.115 13.325 5.418 13.441 ;
     RECT  3.996 13.387 4.014 13.469 ;
     RECT  14.796 13.091 14.814 13.469 ;
     RECT  10.152 13.133 13.842 13.631 ;
     RECT  5.115 13.441 5.922 13.667 ;
     RECT  0.108 9.581 0.198 13.703 ;
     RECT  11.664 13.631 12.366 13.703 ;
     RECT  0.144 13.703 0.198 13.739 ;
     RECT  10.152 13.631 10.797 13.829 ;
     RECT  11.664 13.703 12.258 13.901 ;
     RECT  7.815 13.091 8.73 13.909 ;
     RECT  0.144 13.739 0.162 13.937 ;
     RECT  7.815 13.909 9.162 14.009 ;
     RECT  7.815 14.009 8.658 14.099 ;
     RECT  11.664 13.901 11.682 14.135 ;
     RECT  13.14 13.631 13.842 14.135 ;
     RECT  13.215 14.135 13.842 14.171 ;
     RECT  7.815 14.099 8.55 14.251 ;
     RECT  7.272 14.251 8.55 14.369 ;
     RECT  7.272 14.369 8.154 14.405 ;
     RECT  2.415 12.749 2.697 14.867 ;
     RECT  5.115 13.667 5.397 14.867 ;
     RECT  7.38 14.405 8.097 14.867 ;
     RECT  10.515 13.829 10.797 14.867 ;
     RECT  13.215 14.171 13.497 14.867 ;
     RECT  2.415 14.867 2.505 15.137 ;
     RECT  5.115 14.867 5.205 15.137 ;
     RECT  7.38 14.867 7.905 15.137 ;
     RECT  10.515 14.867 10.605 15.137 ;
     RECT  13.215 14.867 13.305 15.137 ;
     RECT  7.38 15.137 7.398 15.389 ;
    LAYER M4 ;
     RECT  0.06 4.272 2.408 10.344 ;
     RECT  0.06 13.296 2.408 13.416 ;
     RECT  2.408 2.148 2.512 15.132 ;
     RECT  2.512 2.418 2.704 14.862 ;
     RECT  2.704 13.296 4.025 13.416 ;
     RECT  2.704 4.368 5.108 11.208 ;
     RECT  4.025 13.296 5.108 13.32 ;
     RECT  5.108 2.148 5.212 15.132 ;
     RECT  5.212 2.418 5.404 14.862 ;
     RECT  5.404 4.368 5.717 9.336 ;
     RECT  5.404 11.184 6.721 11.208 ;
     RECT  5.717 4.368 6.829 8.52 ;
     RECT  6.829 4.176 6.937 8.52 ;
     RECT  6.649 9.504 6.937 9.528 ;
     RECT  6.721 11.184 7.081 11.304 ;
     RECT  6.865 12.48 7.081 12.504 ;
     RECT  7.081 11.184 7.141 12.504 ;
     RECT  6.937 4.176 7.261 9.528 ;
     RECT  7.237 15.36 7.409 15.384 ;
     RECT  7.261 4.176 7.513 9.816 ;
     RECT  7.141 10.944 7.513 12.504 ;
     RECT  7.513 4.176 7.669 12.504 ;
     RECT  7.669 4.176 7.808 13.08 ;
     RECT  7.261 14.256 7.808 14.28 ;
     RECT  7.808 2.148 7.912 15.132 ;
     RECT  7.912 2.418 8.104 14.862 ;
     RECT  8.104 4.176 10.508 13.08 ;
     RECT  10.508 2.148 10.612 15.132 ;
     RECT  10.612 2.418 10.804 14.862 ;
     RECT  10.804 4.464 11.081 5.832 ;
     RECT  11.081 4.656 11.297 5.832 ;
     RECT  11.297 4.656 11.981 5.592 ;
     RECT  11.981 4.656 12.161 5.208 ;
     RECT  10.804 6.912 13.057 13.416 ;
     RECT  12.161 4.656 13.208 5.064 ;
     RECT  13.057 6.864 13.208 13.416 ;
     RECT  13.208 2.148 13.312 15.132 ;
     RECT  13.312 2.418 13.504 14.862 ;
     RECT  13.504 6.864 13.637 13.32 ;
     RECT  13.637 12.288 13.781 13.32 ;
     RECT  13.781 12.288 13.925 13.128 ;
     RECT  13.637 6.864 14.713 11.256 ;
     RECT  13.925 12.288 14.713 13.08 ;
     RECT  14.713 6.864 17.056 13.08 ;
     RECT  17.056 6.864 17.244 13.128 ;
    LAYER M5 ;
     RECT  2.4 2.137 2.52 2.151 ;
     RECT  5.1 2.137 5.22 2.151 ;
     RECT  7.8 2.137 7.92 2.151 ;
     RECT  10.5 2.137 10.62 2.151 ;
     RECT  13.2 2.137 13.32 2.151 ;
     RECT  0.192 4.885 0.216 5.075 ;
     RECT  2.4 2.151 2.712 5.413 ;
     RECT  2.304 5.413 2.712 5.603 ;
     RECT  13.2 2.151 13.512 7.381 ;
     RECT  13.104 7.381 13.512 7.859 ;
     RECT  10.5 2.151 10.812 7.957 ;
     RECT  7.8 2.151 8.112 9.061 ;
     RECT  0.144 8.917 0.168 9.587 ;
     RECT  7.8 9.061 8.232 10.069 ;
     RECT  7.8 10.069 8.376 10.933 ;
     RECT  13.2 7.859 13.512 11.077 ;
     RECT  13.104 11.077 13.512 11.315 ;
     RECT  10.5 7.957 11.64 11.459 ;
     RECT  7.152 10.933 8.376 12.563 ;
     RECT  2.4 5.603 2.712 15.129 ;
     RECT  5.1 2.151 5.412 15.129 ;
     RECT  7.152 12.563 8.112 15.129 ;
     RECT  10.5 11.459 10.812 15.129 ;
     RECT  13.2 11.315 13.512 15.129 ;
     RECT  2.4 15.129 2.52 15.143 ;
     RECT  5.1 15.129 5.22 15.143 ;
     RECT  7.152 15.129 7.92 15.143 ;
     RECT  10.5 15.129 10.62 15.143 ;
     RECT  13.2 15.129 13.32 15.143 ;
     RECT  7.152 15.143 7.272 17.232 ;
  END
END dsfd_rly_66_EW
END LIBRARY
